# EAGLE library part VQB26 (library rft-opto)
VQB26 RFT VQB 26 (Vorzeichen + 1, grünstrahlend) nach TGL 55111. Bauelementeinformation siehe Funkamateur FA 2/89 Seite 77

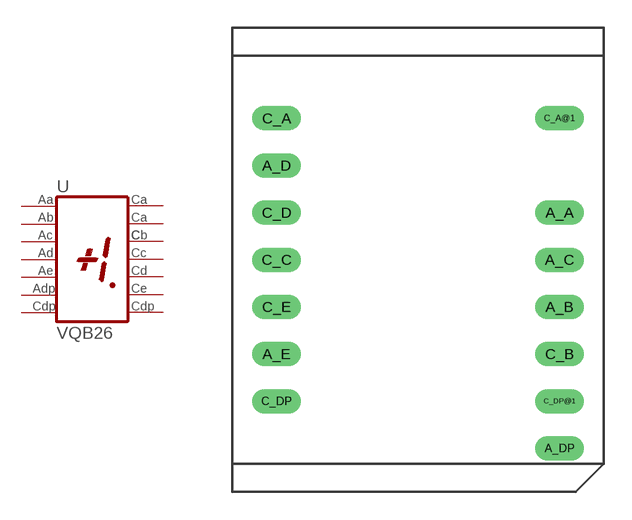
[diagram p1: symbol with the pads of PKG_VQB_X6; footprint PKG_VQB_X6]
Designator prefix -

## VQB26  [PKG_VQB_X6]
A_A  A_A  pas
A_B  A_B  pas
A_C  A_C  pas
A_D  A_D  pas
A_DP  A_DP  pas
A_E  A_E  pas
C_A  C_A  pas
C_A@1  C_A  pas
C_B  C_B  pas
C_C  C_C  pas
C_D  C_D  pas
C_DP  C_DP  pas
C_DP@1  C_DP  pas
C_E  C_E  pas

## Footprint PKG_VQB_X6 (pad centres in mm)
TGL 55111 / VQB x6
drill 0.8 long: A_A 7.62,2.54; A_B 7.62,-2.54; A_C 7.62,0; A_D -7.62,5.08; A_DP 7.62,-10.16; A_E -7.62,-5.08; C_A -7.62,7.62; C_A@1 7.62,7.62; C_B 7.62,-5.08; C_C -7.62,0; C_D -7.62,2.54; C_DP -7.62,-7.62; C_DP@1 7.62,-7.62; C_E -7.62,-2.54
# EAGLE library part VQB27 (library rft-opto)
VQB27 RFT VQB 27 (7 Segmentanzeige mit DP, gemeinsame Katode, grünstrahlend) nach TGL 55111. Bauelementeinformation siehe Funkamateur FA 2/89 Seite 77

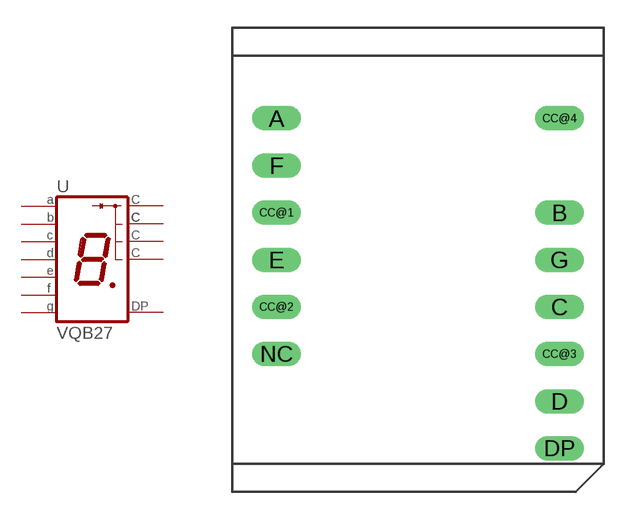
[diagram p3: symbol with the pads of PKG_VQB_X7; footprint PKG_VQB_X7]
Designator prefix -

## VQB27  [PKG_VQB_X7]
A  A  pas
B  B  pas
C  C  pas
CC@1  C  pas
CC@2  C  pas
CC@3  C  pas
CC@4  C  pas
D  D  pas
DP  DP  pas
E  E  pas
F  F  pas
G  G  pas

## Footprint PKG_VQB_X7 (pad centres in mm)
TGL 55111 / VQB x7
drill 0.8 long: A -7.62,7.62; B 7.62,2.54; C 7.62,-2.54; CC@1 -7.62,2.54; CC@2 -7.62,-2.54; CC@3 7.62,-5.08; CC@4 7.62,7.62; D 7.62,-7.62; DP 7.62,-10.16; E -7.62,0; F -7.62,5.08; G 7.62,0; NC -7.62,-5.08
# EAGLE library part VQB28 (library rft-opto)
VQB28 RFT VQB 28 (7 Segmentanzeige mit DP, gemeinsame Anode, grünstrahlend) nach TGL 55111. Bauelementeinformation siehe Funkamateur FA 2/89 Seite 77

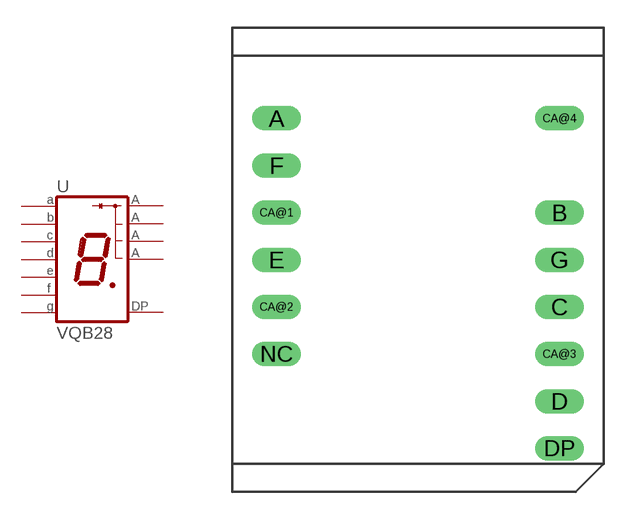
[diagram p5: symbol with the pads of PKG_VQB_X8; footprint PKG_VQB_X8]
Designator prefix -

## VQB28  [PKG_VQB_X8]
A  A  pas
B  B  pas
C  C  pas
CA@1  CA  pas
CA@2  CA  pas
CA@3  CA  pas
CA@4  CA  pas
D  D  pas
DP  DP  pas
E  E  pas
F  F  pas
G  G  pas

## Footprint PKG_VQB_X8 (pad centres in mm)
TGL 55111 / VQB x8
drill 0.8 long: A -7.62,7.62; B 7.62,2.54; C 7.62,-2.54; CA@1 -7.62,2.54; CA@2 -7.62,-2.54; CA@3 7.62,-5.08; CA@4 7.62,7.62; D 7.62,-7.62; DP 7.62,-10.16; E -7.62,0; F -7.62,5.08; G 7.62,0; NC -7.62,-5.08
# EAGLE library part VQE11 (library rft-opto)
VQE11 RFT VQE 11 (1 1/2 stellige 7-Segment-Anzeige mit Vorzeichen und gemeinsamer Katode, rotstrahlend) nach TGL 55110. Bauelementeinformation siehe Funkamateur FA 3/90 Seite 131

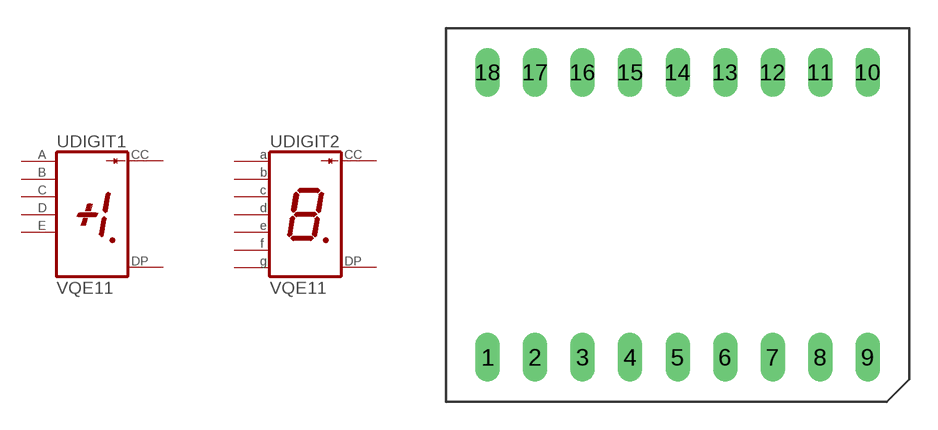
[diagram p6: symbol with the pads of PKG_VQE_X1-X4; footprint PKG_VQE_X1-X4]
Designator prefix -; gates DIGIT1=SYM_VQEX1A DIGIT2=SYM_VQEX1B

## VQE11  [PKG_VQE_X1-X4]
2  DIGIT1:DP1  pas
3  DIGIT1:B1  pas
4  DIGIT1:CC1  pas
5  DIGIT2:CC2  pas
6  DIGIT2:D2  pas
7  DIGIT2:E2  pas
8  DIGIT2:C2  pas
9  DIGIT2:DP2  pas
10  DIGIT2:G2  pas
11  DIGIT2:A2  pas
12  DIGIT2:F2  pas
13  DIGIT2:B2  pas
14  DIGIT1:A1  pas
15  DIGIT1:E1  pas
16  DIGIT1:C1  pas
17  DIGIT1:D1  pas

## Footprint PKG_VQE_X1-X4 (pad centres in mm)
TGL 55110 & TGL 39352 / VQE 11, 12, 13, 14, 21, 22, 23, 24
drill 0.8 long: 1 -10.16,-7.62; 2 -7.62,-7.62; 3 -5.08,-7.62; 4 -2.54,-7.62; 5 0,-7.62; 6 2.54,-7.62; 7 5.08,-7.62; 8 7.62,-7.62; 9 10.16,-7.62; 10 10.16,7.62; 11 7.62,7.62; 12 5.08,7.62; 13 2.54,7.62; 14 0,7.62; 15 -2.54,7.62; 16 -5.08,7.62; 17 -7.62,7.62; 18 -10.16,7.62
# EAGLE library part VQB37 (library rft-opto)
VQB37 RFT VQB 37 (7-Segment-Miniatur-Anzeige mit gemeinsamer Katode und Linse, rotstrahlend) nach TGL 32989.

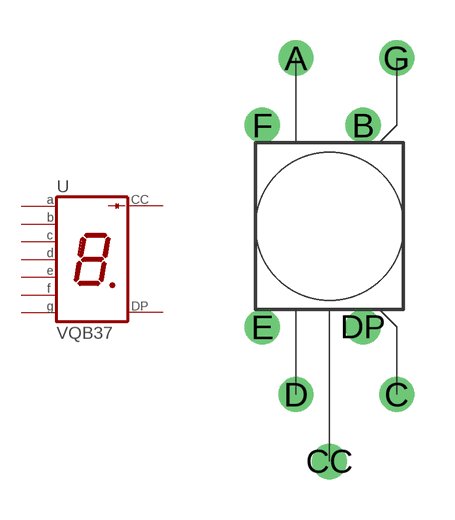
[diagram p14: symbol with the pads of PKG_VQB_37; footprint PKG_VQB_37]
Designator prefix -

## VQB37  [PKG_VQB_37]
A  A  pas
B  B  pas
C  C  pas
CC  CC  pas
D  D  pas
DP  DP  pas
E  E  pas
F  F  pas
G  G  pas

## Footprint PKG_VQB_37 (pad centres in mm)
TGL 32989 / VQB 37
drill 0.8 round: A -1.25,6.25; B 1.25,3.75; C 2.5,-6.25; CC 0,-8.75; D -1.25,-6.25; DP 1.25,-3.75; E -2.5,-3.75; F -2.5,3.75; G 2.5,6.25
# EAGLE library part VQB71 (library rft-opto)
VQB71 RFT VQB 71 (7-Segment-Anzeige mit gemeinsamer Anode und Dezimalpunkt, rotstrahlend) nach TGL 31245.

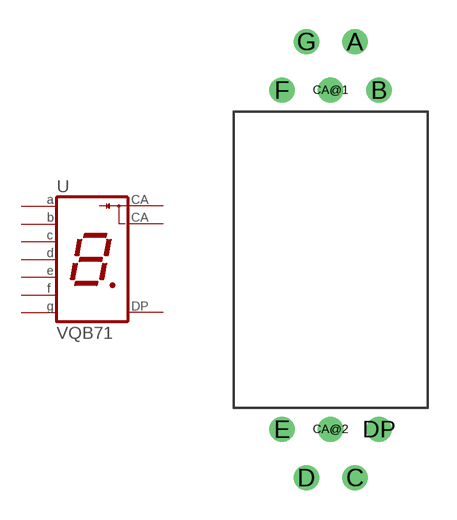
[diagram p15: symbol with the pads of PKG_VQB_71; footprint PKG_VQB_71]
Designator prefix -

## VQB71  [PKG_VQB_71]
A  A  pas
B  B  pas
C  C  pas
CA@1  CA  pas
CA@2  CA  pas
D  D  pas
DP  DP  pas
E  E  pas
F  F  pas
G  G  pas

## Footprint PKG_VQB_71 (pad centres in mm)
TGL 31245 / VQB 71
drill 0.8 round: A 1.25,11.25; B 2.5,8.75; C 1.25,-11.25; CA@1 0,8.75; CA@2 0,-8.75; D -1.25,-11.25; DP 2.5,-8.75; E -2.5,-8.75; F -2.5,8.75; G -1.25,11.25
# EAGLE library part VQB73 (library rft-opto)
VQB73 RFT VQB 73 (4-Segment Vorzeichen Anzeige mit gemeinsamer Anode, rotstrahlend) nach TGL 31245.

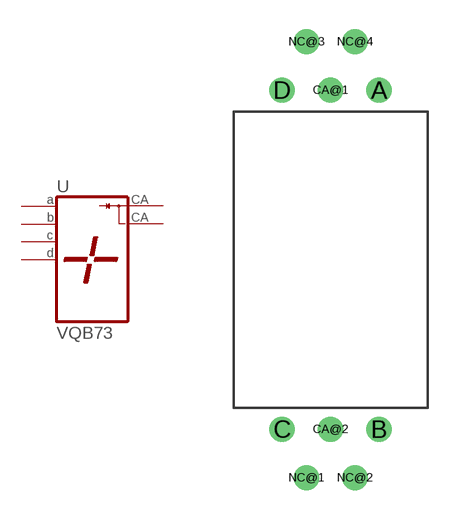
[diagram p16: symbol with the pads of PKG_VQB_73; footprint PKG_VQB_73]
Designator prefix -

## VQB73  [PKG_VQB_73]
A  A  pas
B  B  pas
C  C  pas
CA@1  CA  pas
CA@2  CA  pas
D  D  pas

## Footprint PKG_VQB_73 (pad centres in mm)
TGL 31245 / VQB 73
drill 0.8 round: A 2.5,8.75; B 2.5,-8.75; C -2.5,-8.75; CA@1 0,8.75; CA@2 0,-8.75; D -2.5,8.75; NC@1 -1.25,-11.25; NC@2 1.25,-11.25; NC@3 -1.25,11.25; NC@4 1.25,11.25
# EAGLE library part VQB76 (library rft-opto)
VQB76 RFT VQB 76 (7-Segment-Anzeige in DIL Format mit Dezimalpunkt, rotstrahlend). Entweder mit rotem Filter (VQB 76) oder mit klarem Filter (VQB 76/1)

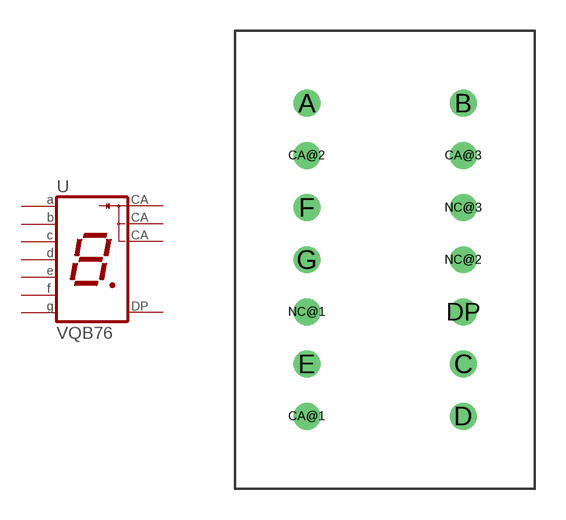
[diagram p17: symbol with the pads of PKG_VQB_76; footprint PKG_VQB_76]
Designator prefix -

## VQB76  [PKG_VQB_76]
A  A  pas
B  B  pas
C  C  pas
CA@1  CA  pas
CA@2  CA  pas
CA@3  CA  pas
D  D  pas
DP  DP  pas
E  E  pas
F  F  pas
G  G  pas

## Footprint PKG_VQB_76 (pad centres in mm)
drill 0.8 round: A -3.81,7.62; B 3.81,7.62; C 3.81,-5.08; CA@1 -3.81,-7.62; CA@2 -3.81,5.08; CA@3 3.81,5.08; D 3.81,-7.62; DP 3.81,-2.54; E -3.81,-5.08; F -3.81,2.54; G -3.81,0; NC@1 -3.81,-2.54; NC@2 3.81,0; NC@3 3.81,2.54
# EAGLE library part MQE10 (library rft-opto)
MQE10 RFT MQE 10 (3-fach 7-Segment-Anzeige mit integrierten A/D Wandler (C 520)) Eingangspannung von -90 mV bis +999 mV, Auflösung 1 mV PinNameBeschreibung 1DIGIT2Multiplexausgang MSD 2nicht herausgeführt 3DP2Katode Dezimalpunkt MSD 4DIMHelligkeitsregelung 5DIGIT1Multiplexausgang NSD 6DP1Katode Dezimalpunkt NSD 7nicht herausgeführt 8BCD_DBCD-Ausgang D (Qd) 9BCD_CBCD-Ausgang C (Qc) 10BCD_BBCD-Ausgang B (Qb) 11BCD_ABCD-Ausgang A (Qa) 12DIGIT0Multiplexausgang LSD 13nicht herausgeführt 14DP0Katode Dezimalpunkt LSD 15VCCVersorgungspannung (5V) 16GNDMasse 17GNDMasse 18GNDMasse 19GNDMasse 20GNDMasse 21GNDMasse 22C_JIntegrationskondensator Cj 23RATEUmsetzrate/Geschwindigkeit Wandlung 24NP_1Nullpunkt-Abgleich 25NP_2Nullpunkt-Abgleich 26IN_LEingang Low 27IN_HEingang High 28EWEndwert-Abgleich

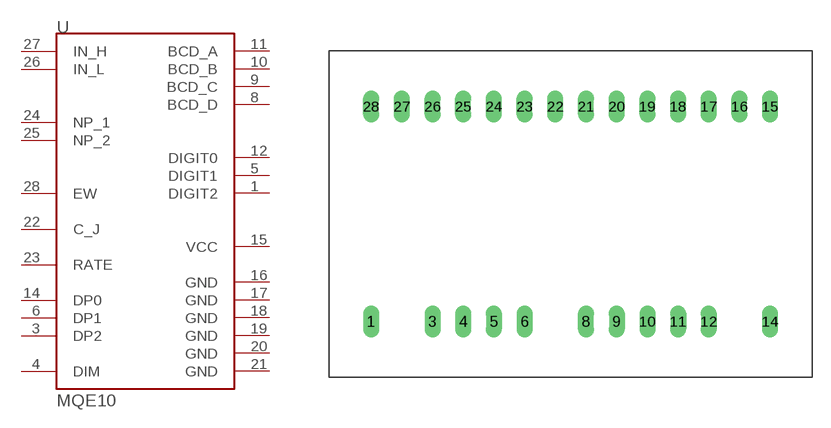
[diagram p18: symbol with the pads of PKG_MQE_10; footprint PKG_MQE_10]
Designator prefix -

## MQE10  [PKG_MQE_10]
1  DIGIT2  out
3  DP2  pas
4  DIM  pas
5  DIGIT1  out
6  DP1  pas
8  BCD_D  out
9  BCD_C  out
10  BCD_B  out
11  BCD_A  out
12  DIGIT0  out
14  DP0  pas
15  VCC  pwr
16  GND  sup
17  GND  sup
18  GND  sup
19  GND  sup
20  GND  sup
21  GND  sup
22  C_J  pas
23  RATE  pas
24  NP_1  pas
25  NP_2  pas
26  IN_L  in
27  IN_H  in
28  EW  pas

## Footprint PKG_MQE_10 (pad centres in mm)
RFT MQE 10
drill 0.8 long: 1 -16.51,-8.89; 3 -11.43,-8.89; 4 -8.89,-8.89; 5 -6.35,-8.89; 6 -3.81,-8.89; 8 1.27,-8.89; 9 3.81,-8.89; 10 6.35,-8.89; 11 8.89,-8.89; 12 11.43,-8.89; 14 16.51,-8.89; 15 16.51,8.89; 16 13.97,8.89; 17 11.43,8.89; 18 8.89,8.89; 19 6.35,8.89; 20 3.81,8.89; 21 1.27,8.89; 22 -1.27,8.89; 23 -3.81,8.89; 24 -6.35,8.89; 25 -8.89,8.89; 26 -11.43,8.89; 27 -13.97,8.89; 28 -16.51,8.89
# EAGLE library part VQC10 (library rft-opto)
VQC10 RFT VQC 10 (4-stellige 5x7 Puntmatrix, rotstrahlend)

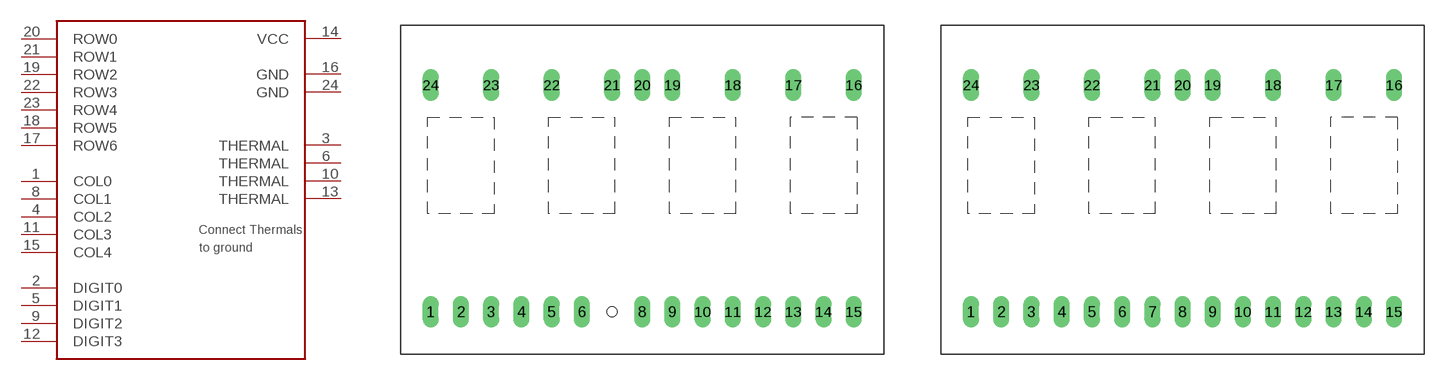
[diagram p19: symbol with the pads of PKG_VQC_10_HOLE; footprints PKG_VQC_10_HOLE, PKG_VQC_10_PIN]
Designator prefix -

## VQC10HOLE  [PKG_VQC_10_HOLE]
1  COL0  pas
2  DIGIT0  pas
3  THERMAL  sup
4  COL2  pas
5  DIGIT1  pas
6  THERMAL  sup
8  COL1  pas
9  DIGIT2  pas
10  THERMAL  sup
11  COL3  pas
12  DIGIT3  pas
13  THERMAL  sup
14  VCC  pwr
15  COL4  pas
16  GND  sup
17  ROW6  pas
18  ROW5  pas
19  ROW2  pas
20  ROW0  pas
21  ROW1  pas
22  ROW3  pas
23  ROW4  pas
24  GND  sup

## VQC10PIN  [PKG_VQC_10_PIN]
Pads as for PKG_VQC_10_HOLE

## Footprint PKG_VQC_10_HOLE (pad centres in mm)
TGL 38469 / VQC 10 Dieses Package führt den intern verbundenen Pin 7 als Bohrloch ohne Lötauge aus.
drill 0.8 long: 1 -17.5,-10.1; 2 -15,-10.1; 3 -12.5,-10.1; 4 -10,-10.1; 5 -7.5,-10.1; 6 -5,-10.1; 8 0,-10.1; 9 2.5,-10.1; 10 5,-10.1; 11 7.5,-10.1; 12 10,-10.1; 13 12.5,-10.1; 14 15,-10.1; 15 17.5,-10.1; 16 17.5,8.65; 17 12.5,8.65; 18 7.5,8.65; 19 2.5,8.65; 20 0,8.65; 21 -2.5,8.65; 22 -7.5,8.65; 23 -12.5,8.65; 24 -17.5,8.65
hole 0.8 at -2.5,-10.1

## Footprint PKG_VQC_10_PIN (pad centres in mm)
TGL 38469 / VQC 10 Dieses Package führt den intern verbundenen Pin 7 als normalen Pin aus.
drill 0.8 long: 1 -17.5,-10.1; 2 -15,-10.1; 3 -12.5,-10.1; 4 -10,-10.1; 5 -7.5,-10.1; 6 -5,-10.1; 7 -2.5,-10.1; 8 0,-10.1; 9 2.5,-10.1; 10 5,-10.1; 11 7.5,-10.1; 12 10,-10.1; 13 12.5,-10.1; 14 15,-10.1; 15 17.5,-10.1; 16 17.5,8.65; 17 12.5,8.65; 18 7.5,8.65; 19 2.5,8.65; 20 0,8.65; 21 -2.5,8.65; 22 -7.5,8.65; 23 -12.5,8.65; 24 -17.5,8.65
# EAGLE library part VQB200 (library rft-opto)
VQB200 RFT VQB 200 (16-Segment-Anzeige mit Dezimalpunkt, grünstrahlend, gemeinsame Katode) nach TGL 42170.

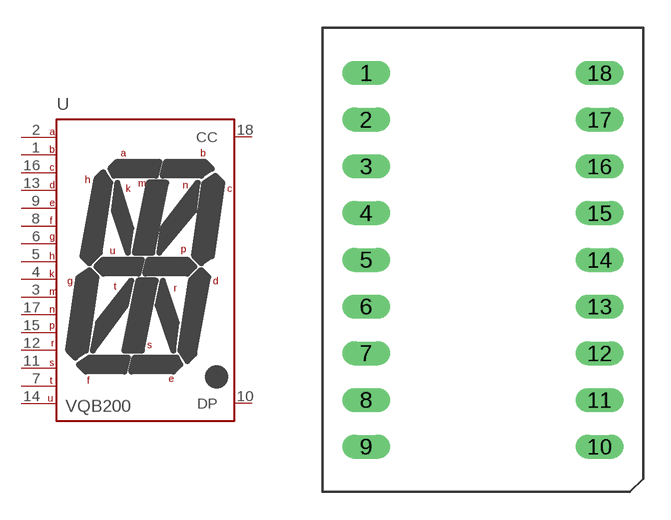
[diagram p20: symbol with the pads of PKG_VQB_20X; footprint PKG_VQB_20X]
Designator prefix -

## VQB200  [PKG_VQB_20X]
1  B  pas
2  A  pas
3  M  pas
4  K  pas
5  H  pas
6  G  pas
7  T  pas
8  F  pas
9  E  pas
10  DP  pas
11  S  pas
12  R  pas
13  D  pas
14  U  pas
15  P  pas
16  C  pas
17  N  pas
18  CC  pas

## Footprint PKG_VQB_20X (pad centres in mm)
TGL 42170 / VQB 200, VQB 201
drill 0.8 long: 1 -6.35,10.16; 2 -6.35,7.62; 3 -6.35,5.08; 4 -6.35,2.54; 5 -6.35,0; 6 -6.35,-2.54; 7 -6.35,-5.08; 8 -6.35,-7.62; 9 -6.35,-10.16; 10 6.35,-10.16; 11 6.35,-7.62; 12 6.35,-5.08; 13 6.35,-2.54; 14 6.35,0; 15 6.35,2.54; 16 6.35,5.08; 17 6.35,7.62; 18 6.35,10.16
